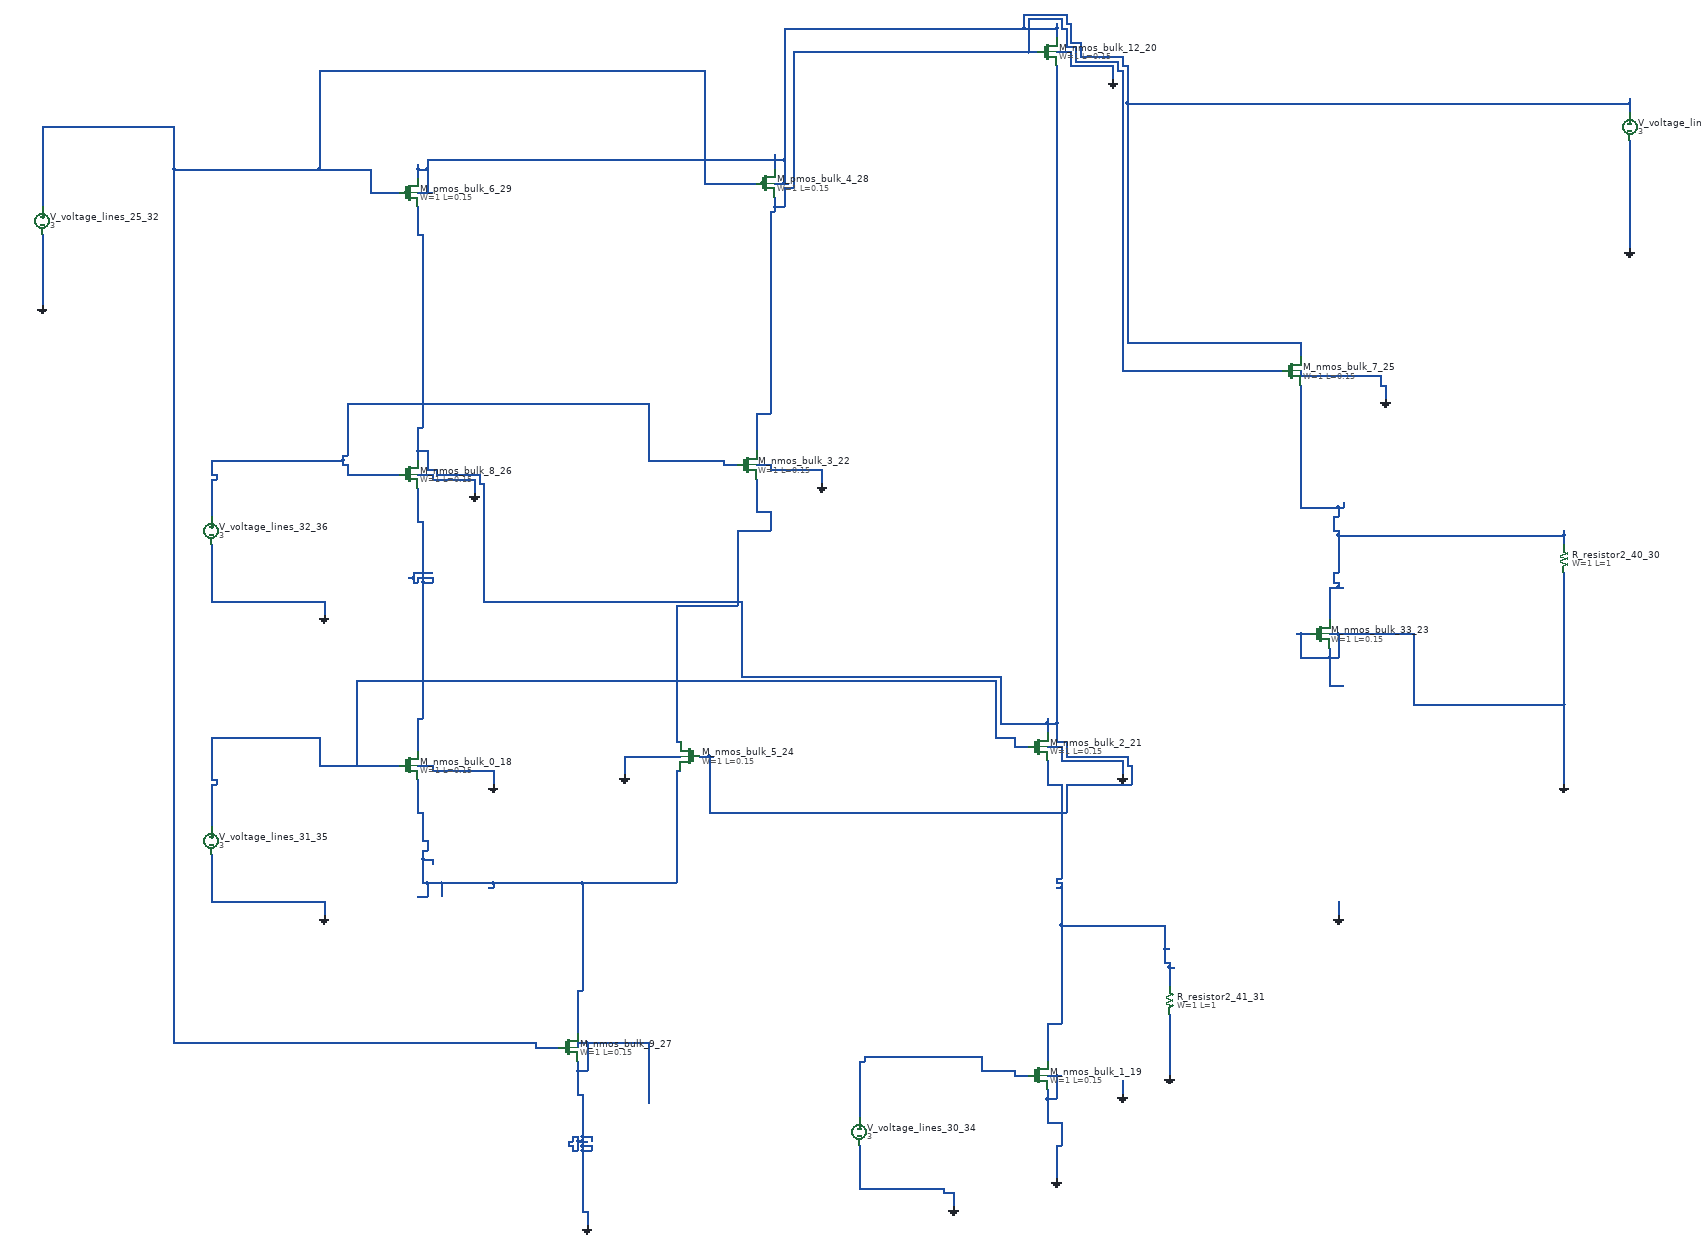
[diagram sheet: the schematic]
v {xschem version=3.4.8 file_version=1.2}
G {}
K {}
V {}
S {}
E {}
C {devices/gnd.sym} 3360 1820 0 0 {name="l_gnd_10_0" lab="GND"}
C {devices/gnd.sym} 1280 2760 0 0 {name="l_gnd_11_1" lab="GND"}
C {devices/gnd.sym} 2520 2440 0 0 {name="l_gnd_13_2" lab="GND"}
C {devices/gnd.sym} 2420 2480 0 0 {name="l_gnd_14_3" lab="GND"}
C {devices/gnd.sym} 1080 1820 0 0 {name="l_gnd_15_4" lab="GND"}
C {devices/gnd.sym} 3500 680 0 0 {name="l_gnd_16_5" lab="GND"}
C {devices/gnd.sym} 2060 2720 0 0 {name="l_gnd_17_6" lab="GND"}
C {devices/gnd.sym} 1780 1180 0 0 {name="l_gnd_18_7" lab="GND"}
C {devices/gnd.sym} 120 800 0 0 {name="l_gnd_19_8" lab="GND"}
C {devices/gnd.sym} 1040 1200 0 0 {name="l_gnd_20_9" lab="GND"}
C {devices/gnd.sym} 720 1460 0 0 {name="l_gnd_21_10" lab="GND"}
C {devices/gnd.sym} 720 2100 0 0 {name="l_gnd_22_11" lab="GND"}
C {devices/gnd.sym} 2880 2100 0 0 {name="l_gnd_23_12" lab="GND"}
C {devices/gnd.sym} 1360 1800 0 0 {name="l_gnd_24_13" lab="GND"}
C {devices/gnd.sym} 2400 320 0 0 {name="l_gnd_27_14" lab="GND"}
C {devices/gnd.sym} 2980 1000 0 0 {name="l_gnd_28_15" lab="GND"}
C {devices/gnd.sym} 2420 1800 0 0 {name="l_gnd_29_16" lab="GND"}
C {devices/gnd.sym} 2280 2660 0 0 {name="l_gnd_34_17" lab="GND"}
C {sky130_fd_pr/nfet_01v8.sym} 900 1780 0 0 {name="M_nmos_bulk_0_18"
W=1
L=0.15
nf=1 
mult=1
ad="expr('int((@nf + 1)/2) * @W / @nf * 0.29')"
pd="expr('2*int((@nf + 1)/2) * (@W / @nf + 0.29)')"
as="expr('int((@nf + 2)/2) * @W / @nf * 0.29')"
ps="expr('2*int((@nf + 2)/2) * (@W / @nf + 0.29)')"
nrd="expr('0.29 / @W ')" nrs="expr('0.29 / @W ')"
sa=0 sb=0 sd=0
model=nfet_01v8
spiceprefix=X
}
C {sky130_fd_pr/nfet_01v8.sym} 2240 2440 0 0 {name="M_nmos_bulk_1_19"
W=1
L=0.15
nf=1 
mult=1
ad="expr('int((@nf + 1)/2) * @W / @nf * 0.29')"
pd="expr('2*int((@nf + 1)/2) * (@W / @nf + 0.29)')"
as="expr('int((@nf + 2)/2) * @W / @nf * 0.29')"
ps="expr('2*int((@nf + 2)/2) * (@W / @nf + 0.29)')"
nrd="expr('0.29 / @W ')" nrs="expr('0.29 / @W ')"
sa=0 sb=0 sd=0
model=nfet_01v8
spiceprefix=X
}
C {sky130_fd_pr/nfet_01v8.sym} 2260 260 0 0 {name="M_nmos_bulk_12_20"
W=1
L=0.15
nf=1 
mult=1
ad="expr('int((@nf + 1)/2) * @W / @nf * 0.29')"
pd="expr('2*int((@nf + 1)/2) * (@W / @nf + 0.29)')"
as="expr('int((@nf + 2)/2) * @W / @nf * 0.29')"
ps="expr('2*int((@nf + 2)/2) * (@W / @nf + 0.29)')"
nrd="expr('0.29 / @W ')" nrs="expr('0.29 / @W ')"
sa=0 sb=0 sd=0
model=nfet_01v8
spiceprefix=X
}
C {sky130_fd_pr/nfet_01v8.sym} 2240 1740 0 0 {name="M_nmos_bulk_2_21"
W=1
L=0.15
nf=1 
mult=1
ad="expr('int((@nf + 1)/2) * @W / @nf * 0.29')"
pd="expr('2*int((@nf + 1)/2) * (@W / @nf + 0.29)')"
as="expr('int((@nf + 2)/2) * @W / @nf * 0.29')"
ps="expr('2*int((@nf + 2)/2) * (@W / @nf + 0.29)')"
nrd="expr('0.29 / @W ')" nrs="expr('0.29 / @W ')"
sa=0 sb=0 sd=0
model=nfet_01v8
spiceprefix=X
}
C {sky130_fd_pr/nfet_01v8.sym} 1620 1140 0 0 {name="M_nmos_bulk_3_22"
W=1
L=0.15
nf=1 
mult=1
ad="expr('int((@nf + 1)/2) * @W / @nf * 0.29')"
pd="expr('2*int((@nf + 1)/2) * (@W / @nf + 0.29)')"
as="expr('int((@nf + 2)/2) * @W / @nf * 0.29')"
ps="expr('2*int((@nf + 2)/2) * (@W / @nf + 0.29)')"
nrd="expr('0.29 / @W ')" nrs="expr('0.29 / @W ')"
sa=0 sb=0 sd=0
model=nfet_01v8
spiceprefix=X
}
C {sky130_fd_pr/nfet_01v8.sym} 2840 1500 0 0 {name="M_nmos_bulk_33_23"
W=1
L=0.15
nf=1 
mult=1
ad="expr('int((@nf + 1)/2) * @W / @nf * 0.29')"
pd="expr('2*int((@nf + 1)/2) * (@W / @nf + 0.29)')"
as="expr('int((@nf + 2)/2) * @W / @nf * 0.29')"
ps="expr('2*int((@nf + 2)/2) * (@W / @nf + 0.29)')"
nrd="expr('0.29 / @W ')" nrs="expr('0.29 / @W ')"
sa=0 sb=0 sd=0
model=nfet_01v8
spiceprefix=X
}
C {sky130_fd_pr/nfet_01v8.sym} 1500 1760 0 1 {name="M_nmos_bulk_5_24"
W=1
L=0.15
nf=1 
mult=1
ad="expr('int((@nf + 1)/2) * @W / @nf * 0.29')"
pd="expr('2*int((@nf + 1)/2) * (@W / @nf + 0.29)')"
as="expr('int((@nf + 2)/2) * @W / @nf * 0.29')"
ps="expr('2*int((@nf + 2)/2) * (@W / @nf + 0.29)')"
nrd="expr('0.29 / @W ')" nrs="expr('0.29 / @W ')"
sa=0 sb=0 sd=0
model=nfet_01v8
spiceprefix=X
}
C {sky130_fd_pr/nfet_01v8.sym} 2780 940 0 0 {name="M_nmos_bulk_7_25"
W=1
L=0.15
nf=1 
mult=1
ad="expr('int((@nf + 1)/2) * @W / @nf * 0.29')"
pd="expr('2*int((@nf + 1)/2) * (@W / @nf + 0.29)')"
as="expr('int((@nf + 2)/2) * @W / @nf * 0.29')"
ps="expr('2*int((@nf + 2)/2) * (@W / @nf + 0.29)')"
nrd="expr('0.29 / @W ')" nrs="expr('0.29 / @W ')"
sa=0 sb=0 sd=0
model=nfet_01v8
spiceprefix=X
}
C {sky130_fd_pr/nfet_01v8.sym} 900 1160 0 0 {name="M_nmos_bulk_8_26"
W=1
L=0.15
nf=1 
mult=1
ad="expr('int((@nf + 1)/2) * @W / @nf * 0.29')"
pd="expr('2*int((@nf + 1)/2) * (@W / @nf + 0.29)')"
as="expr('int((@nf + 2)/2) * @W / @nf * 0.29')"
ps="expr('2*int((@nf + 2)/2) * (@W / @nf + 0.29)')"
nrd="expr('0.29 / @W ')" nrs="expr('0.29 / @W ')"
sa=0 sb=0 sd=0
model=nfet_01v8
spiceprefix=X
}
C {sky130_fd_pr/nfet_01v8.sym} 1240 2380 0 0 {name="M_nmos_bulk_9_27"
W=1
L=0.15
nf=1 
mult=1
ad="expr('int((@nf + 1)/2) * @W / @nf * 0.29')"
pd="expr('2*int((@nf + 1)/2) * (@W / @nf + 0.29)')"
as="expr('int((@nf + 2)/2) * @W / @nf * 0.29')"
ps="expr('2*int((@nf + 2)/2) * (@W / @nf + 0.29)')"
nrd="expr('0.29 / @W ')" nrs="expr('0.29 / @W ')"
sa=0 sb=0 sd=0
model=nfet_01v8
spiceprefix=X
}
C {sky130_fd_pr/pfet_01v8.sym} 1660 540 0 0 {name="M_pmos_bulk_4_28"
W=1
L=0.15
nf=1
mult=1
ad="expr('int((@nf + 1)/2) * @W / @nf * 0.29')"
pd="expr('2*int((@nf + 1)/2) * (@W / @nf + 0.29)')"
as="expr('int((@nf + 2)/2) * @W / @nf * 0.29')"
ps="expr('2*int((@nf + 2)/2) * (@W / @nf + 0.29)')"
nrd="expr('0.29 / @W ')" nrs="expr('0.29 / @W ')"
sa=0 sb=0 sd=0
model=pfet_01v8
spiceprefix=X
}
C {sky130_fd_pr/pfet_01v8.sym} 900 560 0 0 {name="M_pmos_bulk_6_29"
W=1
L=0.15
nf=1
mult=1
ad="expr('int((@nf + 1)/2) * @W / @nf * 0.29')"
pd="expr('2*int((@nf + 1)/2) * (@W / @nf + 0.29)')"
as="expr('int((@nf + 2)/2) * @W / @nf * 0.29')"
ps="expr('2*int((@nf + 2)/2) * (@W / @nf + 0.29)')"
nrd="expr('0.29 / @W ')" nrs="expr('0.29 / @W ')"
sa=0 sb=0 sd=0
model=pfet_01v8
spiceprefix=X
}
C {sky130_fd_pr/res_generic_po.sym} 3360 1340 0 0 {name="R_resistor2_40_30"
W=1
L=1
model=res_generic_po
spiceprefix=X
mult=1}
C {sky130_fd_pr/res_generic_po.sym} 2520 2280 0 0 {name="R_resistor2_41_31"
W=1
L=1
model=res_generic_po
spiceprefix=X
mult=1}
C {devices/vsource.sym} 120 620 0 0 {name="V_voltage_lines_25_32" value=3 savecurrent=false}
C {devices/vsource.sym} 3500 420 0 0 {name="V_voltage_lines_26_33" value=3 savecurrent=false}
C {devices/vsource.sym} 1860 2560 0 0 {name="V_voltage_lines_30_34" value=3 savecurrent=false}
C {devices/vsource.sym} 480 1940 0 0 {name="V_voltage_lines_31_35" value=3 savecurrent=false}
C {devices/vsource.sym} 480 1280 0 0 {name="V_voltage_lines_32_36" value=3 savecurrent=false}
N 1270 2730 1280 2730 {}
N 2040 2690 2060 2690 {}
N 1860 2680 2040 2680 {}
N 1250 2600 1260 2600 {}
N 1270 2600 1290 2600 {}
N 1240 2590 1250 2590 {}
N 1270 2590 1290 2590 {}
N 2280 2590 2290 2590 {}
N 1240 2580 1250 2580 {}
N 1260 2580 1270 2580 {}
N 1270 2580 1280 2580 {}
N 1250 2570 1260 2570 {}
N 1270 2570 1290 2570 {}
N 2260 2540 2290 2540 {}
N 2260 2490 2280 2490 {}
N 1260 2480 1270 2480 {}
N 2260 2440 2280 2440 {}
N 2280 2440 2290 2440 {}
N 1260 2430 1280 2430 {}
N 1260 2370 1280 2370 {}
N 1280 2370 1410 2370 {}
N 480 2070 720 2070 {}
N 950 1790 1080 1790 {}
N 920 1780 950 1780 {}
N 2290 1770 2420 1770 {}
N 1360 1760 1480 1760 {}
N 2260 1740 2290 1740 {}
N 3040 1650 3360 1650 {}
N 2860 1610 2890 1610 {}
N 2800 1550 2860 1550 {}
N 2860 1550 2880 1550 {}
N 2790 1500 2800 1500 {}
N 2800 1500 2820 1500 {}
N 2860 1500 2880 1500 {}
N 2880 1500 3040 1500 {}
N 480 1430 720 1430 {}
N 950 1170 1040 1170 {}
N 920 1160 950 1160 {}
N 1670 1150 1780 1150 {}
N 1640 1140 1670 1140 {}
N 2970 970 2980 970 {}
N 2800 950 2970 950 {}
N 2310 290 2400 290 {}
N 2280 260 2310 260 {}
N 120 800 120 650 {}
N 480 2070 480 1970 {}
N 480 1430 480 1310 {}
N 720 2100 720 2070 {}
N 720 1460 720 1430 {}
N 950 1790 950 1780 {}
N 950 1170 950 1160 {}
N 1040 1200 1040 1170 {}
N 1080 1820 1080 1790 {}
N 1240 2590 1240 2580 {}
N 1250 2600 1250 2590 {}
N 1250 2580 1250 2570 {}
N 1260 2600 1260 2580 {}
N 1260 2580 1260 2570 {}
N 1260 2480 1260 2430 {}
N 1260 2430 1260 2410 {}
N 1260 2380 1260 2370 {}
N 1270 2730 1270 2600 {}
N 1270 2600 1270 2590 {}
N 1270 2590 1270 2580 {}
N 1270 2580 1270 2570 {}
N 1270 2570 1270 2480 {}
N 1280 2760 1280 2730 {}
N 1280 2430 1280 2370 {}
N 1290 2600 1290 2590 {}
N 1290 2580 1290 2570 {}
N 1360 1800 1360 1760 {}
N 1410 2500 1410 2370 {}
N 1670 1150 1670 1140 {}
N 1780 1180 1780 1150 {}
N 1860 2680 1860 2590 {}
N 2040 2690 2040 2680 {}
N 2060 2720 2060 2690 {}
N 2260 2540 2260 2490 {}
N 2260 2490 2260 2470 {}
N 2280 2660 2280 2590 {}
N 2280 2490 2280 2440 {}
N 2290 2590 2290 2540 {}
N 2290 1770 2290 1740 {}
N 2310 290 2310 260 {}
N 2400 320 2400 290 {}
N 2420 2480 2420 2450 {}
N 2420 1800 2420 1770 {}
N 2520 2440 2520 2310 {}
N 2800 1550 2800 1500 {}
N 2800 950 2800 940 {}
N 2860 1610 2860 1550 {}
N 2860 1550 2860 1530 {}
N 2880 2100 2880 2070 {}
N 2880 1550 2880 1500 {}
N 2970 970 2970 950 {}
N 2980 1000 2980 970 {}
N 3040 1650 3040 1500 {}
N 3360 1820 3360 1650 {}
N 3360 1650 3360 1370 {}
N 3500 680 3500 450 {}
N 480 1820 490 1820 {}
N 480 1810 490 1810 {}
N 710 1780 790 1780 {}
N 790 1780 880 1780 {}
N 2190 1740 2220 1740 {}
N 480 1720 710 1720 {}
N 2150 1720 2190 1720 {}
N 790 1600 2150 1600 {}
N 480 1910 480 1820 {}
N 480 1810 480 1720 {}
N 490 1820 490 1810 {}
N 710 1780 710 1720 {}
N 790 1780 790 1600 {}
N 2150 1720 2150 1600 {}
N 2190 1740 2190 1720 {}
N 1170 2380 1220 2380 {}
N 400 2370 1170 2370 {}
N 820 560 880 560 {}
N 1530 540 1640 540 {}
N 400 510 710 510 {}
N 710 510 820 510 {}
N 120 420 400 420 {}
N 710 300 1530 300 {}
N 120 590 120 420 {}
N 400 2370 400 510 {}
N 400 510 400 420 {}
N 710 510 710 300 {}
N 820 560 820 510 {}
N 1170 2380 1170 2370 {}
N 1530 540 1530 300 {}
N 1540 1880 2300 1880 {}
N 2300 1820 2440 1820 {}
N 2430 1780 2440 1780 {}
N 1520 1760 1540 1760 {}
N 1540 1760 1550 1760 {}
N 2300 1760 2430 1760 {}
N 2280 1730 2300 1730 {}
N 2160 1690 2260 1690 {}
N 2260 1690 2280 1690 {}
N 1610 1590 2160 1590 {}
N 1060 1430 1610 1430 {}
N 1050 1180 1060 1180 {}
N 960 1160 1050 1160 {}
N 940 1150 960 1150 {}
N 920 1110 940 1110 {}
N 920 1060 930 1060 {}
N 920 650 930 650 {}
N 920 1130 920 1110 {}
N 920 1110 920 1060 {}
N 920 650 920 590 {}
N 930 1060 930 650 {}
N 940 1150 940 1110 {}
N 960 1160 960 1150 {}
N 1050 1180 1050 1160 {}
N 1060 1430 1060 1180 {}
N 1540 1880 1540 1760 {}
N 1610 1590 1610 1430 {}
N 2160 1690 2160 1590 {}
N 2260 1710 2260 1690 {}
N 2260 1690 2260 1680 {}
N 2280 1730 2280 1690 {}
N 2280 1690 2280 290 {}
N 2300 1880 2300 1820 {}
N 2300 1760 2300 1730 {}
N 2430 1780 2430 1760 {}
N 2440 1820 2440 1780 {}
N 1640 1030 1670 1030 {}
N 2420 940 2760 940 {}
N 1670 600 1680 600 {}
N 1680 590 1700 590 {}
N 1700 550 1720 550 {}
N 2410 300 2420 300 {}
N 2320 280 2410 280 {}
N 1720 260 2220 260 {}
N 2220 260 2240 260 {}
N 2300 250 2320 250 {}
N 2290 210 2300 210 {}
N 2220 190 2290 190 {}
N 1640 1110 1640 1030 {}
N 1670 1030 1670 600 {}
N 1680 600 1680 590 {}
N 1680 590 1680 570 {}
N 1700 590 1700 550 {}
N 1720 550 1720 260 {}
N 2220 260 2220 190 {}
N 2290 210 2290 190 {}
N 2300 250 2300 210 {}
N 2320 280 2320 250 {}
N 2410 300 2410 280 {}
N 2420 940 2420 300 {}
N 2190 2440 2220 2440 {}
N 2120 2430 2190 2430 {}
N 1860 2410 1870 2410 {}
N 1870 2400 2120 2400 {}
N 1860 2530 1860 2410 {}
N 1870 2410 1870 2400 {}
N 2120 2430 2120 2400 {}
N 2190 2440 2190 2430 {}
N 2260 2330 2290 2330 {}
N 2520 2210 2530 2210 {}
N 2510 2200 2520 2200 {}
N 2510 2170 2520 2170 {}
N 2290 2120 2510 2120 {}
N 2280 2040 2290 2040 {}
N 2280 2030 2290 2030 {}
N 2280 2020 2290 2020 {}
N 2260 1820 2290 1820 {}
N 2260 2410 2260 2330 {}
N 2260 1820 2260 1770 {}
N 2280 2030 2280 2020 {}
N 2290 2330 2290 2120 {}
N 2290 2120 2290 2040 {}
N 2290 2040 2290 2030 {}
N 2290 2020 2290 1820 {}
N 2510 2200 2510 2170 {}
N 2510 2170 2510 2120 {}
N 2520 2250 2520 2210 {}
N 2520 2210 2520 2200 {}
N 480 1170 490 1170 {}
N 480 1160 490 1160 {}
N 770 1160 880 1160 {}
N 760 1140 770 1140 {}
N 1570 1140 1600 1140 {}
N 480 1130 760 1130 {}
N 1410 1130 1570 1130 {}
N 760 1120 770 1120 {}
N 770 1010 1410 1010 {}
N 480 1250 480 1170 {}
N 480 1160 480 1130 {}
N 490 1170 490 1160 {}
N 760 1140 760 1130 {}
N 760 1130 760 1120 {}
N 770 1160 770 1140 {}
N 770 1120 770 1010 {}
N 1410 1130 1410 1010 {}
N 1570 1140 1570 1130 {}
N 1260 2260 1270 2260 {}
N 920 2060 940 2060 {}
N 1070 2040 1080 2040 {}
N 930 2030 940 2030 {}
N 940 2030 970 2030 {}
N 970 2030 1080 2030 {}
N 1080 2030 1270 2030 {}
N 1270 2030 1470 2030 {}
N 930 1980 950 1980 {}
N 930 1960 940 1960 {}
N 930 1940 940 1940 {}
N 920 1880 930 1880 {}
N 1470 1790 1480 1790 {}
N 920 1880 920 1810 {}
N 930 2030 930 1980 {}
N 930 1980 930 1960 {}
N 930 1940 930 1880 {}
N 940 2060 940 2030 {}
N 940 1960 940 1940 {}
N 950 1990 950 1980 {}
N 970 2060 970 2030 {}
N 1080 2040 1080 2030 {}
N 1260 2350 1260 2260 {}
N 1270 2260 1270 2030 {}
N 1470 2030 1470 1790 {}
N 1470 1730 1480 1730 {}
N 1470 1440 1600 1440 {}
N 1600 1280 1670 1280 {}
N 1640 1240 1670 1240 {}
N 1470 1730 1470 1440 {}
N 1600 1440 1600 1280 {}
N 1640 1240 1640 1170 {}
N 1670 1280 1670 1240 {}
N 2430 880 2800 880 {}
N 920 560 940 560 {}
N 940 560 950 560 {}
N 1680 540 1700 540 {}
N 1700 540 1710 540 {}
N 920 510 940 510 {}
N 940 490 1680 490 {}
N 1680 490 1700 490 {}
N 2430 370 3500 370 {}
N 2420 290 2430 290 {}
N 2330 270 2420 270 {}
N 2310 240 2330 240 {}
N 1700 210 2210 210 {}
N 2210 210 2280 210 {}
N 2300 200 2310 200 {}
N 2210 180 2300 180 {}
N 920 530 920 510 {}
N 920 510 920 500 {}
N 940 560 940 510 {}
N 940 510 940 490 {}
N 1680 510 1680 490 {}
N 1680 490 1680 480 {}
N 1700 540 1700 490 {}
N 1700 490 1700 210 {}
N 2210 210 2210 180 {}
N 2280 230 2280 210 {}
N 2280 210 2280 200 {}
N 2300 200 2300 180 {}
N 2310 240 2310 200 {}
N 2330 270 2330 240 {}
N 2420 290 2420 270 {}
N 2430 880 2430 370 {}
N 2430 370 2430 290 {}
N 2800 910 2800 880 {}
N 3500 390 3500 370 {}
N 3500 370 3500 360 {}
N 2860 1400 2880 1400 {}
N 2880 1400 2890 1400 {}
N 2870 1390 2880 1390 {}
N 2870 1370 2880 1370 {}
N 2880 1290 3360 1290 {}
N 2870 1280 2880 1280 {}
N 2870 1250 2880 1250 {}
N 2800 1230 2880 1230 {}
N 2880 1230 2890 1230 {}
N 2800 1230 2800 970 {}
N 2860 1470 2860 1400 {}
N 2870 1390 2870 1370 {}
N 2870 1280 2870 1250 {}
N 2880 1400 2880 1390 {}
N 2880 1370 2880 1290 {}
N 2880 1290 2880 1280 {}
N 2880 1250 2880 1230 {}
N 2890 1230 2890 1220 {}
N 3360 1310 3360 1290 {}
N 3360 1290 3360 1280 {}
N 920 1680 930 1680 {}
N 910 1390 920 1390 {}
N 930 1390 950 1390 {}
N 900 1380 910 1380 {}
N 920 1380 930 1380 {}
N 930 1380 950 1380 {}
N 910 1370 930 1370 {}
N 930 1370 950 1370 {}
N 920 1260 930 1260 {}
N 910 1390 910 1380 {}
N 910 1380 910 1370 {}
N 920 1750 920 1680 {}
N 920 1390 920 1380 {}
N 920 1260 920 1190 {}
N 930 1680 930 1390 {}
N 930 1390 930 1380 {}
N 930 1380 930 1370 {}
N 930 1370 930 1260 {}
N 950 1390 950 1380 {}
